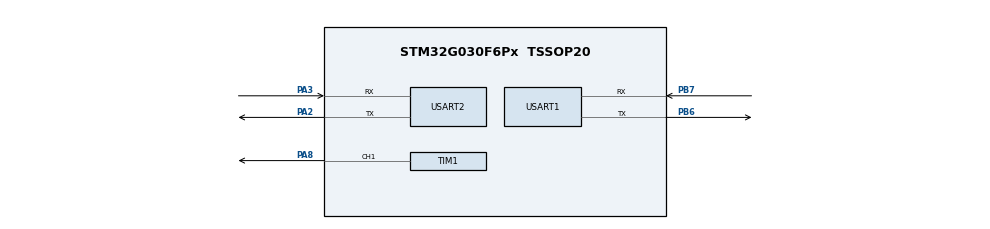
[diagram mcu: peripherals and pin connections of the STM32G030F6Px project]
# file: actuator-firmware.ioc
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Mcu.Family=STM32G0
Mcu.Name=STM32G030F6Px
Mcu.Package=TSSOP20
NVIC.TIM1_BRK_UP_TRG_COM_IRQn=true\:0\:0\:false\:false\:true\:true\:true\:true
PA14-BOOT0__PA15.StandardMode=true
PA2.Mode=Asynchronous
PA2.Signal=USART2_TX
PA3.Mode=Asynchronous
PA3.Signal=USART2_RX
PA8.Signal=S_TIM1_CH1
PB0__PB1__PB2__PA8.StandardMode=true
PB3__PB4__PB5__PB6.StandardMode=true
PB6.Mode=Asynchronous
PB6.Signal=USART1_TX
PB7.Mode=Asynchronous
PB7.Signal=USART1_RX
PB7__PB8.StandardMode=true
PC14-OSC32_IN\ (PC14)__PB9.StandardMode=true
ProjectManager.HeapSize=0x200
ProjectManager.StackSize=0x400
ProjectManager.TargetToolchain=CMake
RCC.ADCFreq_Value=64000000
RCC.AHBFreq_Value=64000000
RCC.CortexFreq_Value=64000000
RCC.EXTERNAL_CLOCK_VALUE=12288000
RCC.HCLKFreq_Value=64000000
RCC.HSE_VALUE=8000000
RCC.HSI_VALUE=16000000
RCC.LSE_VALUE=32768
RCC.SYSCLKFreq_VALUE=64000000
RCC.SYSCLKSource=RCC_SYSCLKSOURCE_PLLCLK
RCC.VCOOutputFreq_Value=128000000
SH.S_TIM1_CH1.0=TIM1_CH1,PWM Generation1 CH1
TIM1.Channel-PWM\ Generation1\ CH1=TIM_CHANNEL_1
TIM1.Period=255
TIM1.Prescaler=16
TIM1.Pulse-PWM\ Generation1\ CH1=0
USART1.VirtualMode-Asynchronous=VM_ASYNC
USART2.VirtualMode-Asynchronous=VM_ASYNC
VP_TIM1_VS_ClockSourceINT.Mode=Internal
board=custom

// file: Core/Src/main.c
/* USER CODE BEGIN Header */
/**
  ******************************************************************************
  * @file           : main.c
  * @brief          : Main program body
  ******************************************************************************
  * @attention
  *
  * Copyright (c) 2025 STMicroelectronics.
  * All rights reserved.
  *
  * This software is licensed under terms that can be found in the LICENSE file
  * in the root directory of this software component.
  * If no LICENSE file comes with this software, it is provided AS-IS.
  *
  ******************************************************************************
  */
/* USER CODE END Header */
#include "main.h"

TIM_HandleTypeDef htim1;

UART_HandleTypeDef huart1;
UART_HandleTypeDef huart2;

void SystemClock_Config(void);
static void MX_GPIO_Init(void);
static void MX_TIM1_Init(void);
static void MX_USART1_UART_Init(void);
static void MX_USART2_UART_Init(void);

/* USER CODE BEGIN 0 */
void real_main(void);

/* USER CODE END 0 */

int main(void)
{

  /* MCU Configuration--------------------------------------------------------*/

  /* Reset of all peripherals, Initializes the Flash interface and the Systick. */
  HAL_Init();

  /* Configure the system clock */
  SystemClock_Config();

  /* Initialize all configured peripherals */
  MX_GPIO_Init();
  MX_TIM1_Init();
  MX_USART1_UART_Init();
  MX_USART2_UART_Init();

  /* Infinite loop */
  while (1)
  {

    /* USER CODE BEGIN 3 */
    real_main();
  }
  /* USER CODE END 3 */
}

void SystemClock_Config(void)
{
  RCC_OscInitTypeDef RCC_OscInitStruct = {0};
  RCC_ClkInitTypeDef RCC_ClkInitStruct = {0};

  /** Configure the main internal regulator output voltage
  */
  HAL_PWREx_ControlVoltageScaling(PWR_REGULATOR_VOLTAGE_SCALE1);

  /** Initializes the RCC Oscillators according to the specified parameters
  * in the RCC_OscInitTypeDef structure.
  */
  RCC_OscInitStruct.OscillatorType = RCC_OSCILLATORTYPE_HSI;
  RCC_OscInitStruct.HSIState = RCC_HSI_ON;
  RCC_OscInitStruct.HSIDiv = RCC_HSI_DIV1;
  RCC_OscInitStruct.HSICalibrationValue = RCC_HSICALIBRATION_DEFAULT;
  RCC_OscInitStruct.PLL.PLLState = RCC_PLL_NONE;
  if (HAL_RCC_OscConfig(&RCC_OscInitStruct) != HAL_OK)
  {
    Error_Handler();
  }

  /** Initializes the CPU, AHB and APB buses clocks
  */
  RCC_ClkInitStruct.ClockType = RCC_CLOCKTYPE_HCLK|RCC_CLOCKTYPE_SYSCLK
                              |RCC_CLOCKTYPE_PCLK1;
  RCC_ClkInitStruct.SYSCLKSource = RCC_SYSCLKSOURCE_HSI;
  RCC_ClkInitStruct.AHBCLKDivider = RCC_SYSCLK_DIV1;
  RCC_ClkInitStruct.APB1CLKDivider = RCC_HCLK_DIV1;

  if (HAL_RCC_ClockConfig(&RCC_ClkInitStruct, FLASH_LATENCY_0) != HAL_OK)
  {
    Error_Handler();
  }
}

static void MX_TIM1_Init(void)
{

  TIM_ClockConfigTypeDef sClockSourceConfig = {0};
  TIM_MasterConfigTypeDef sMasterConfig = {0};
  TIM_OC_InitTypeDef sConfigOC = {0};
  TIM_BreakDeadTimeConfigTypeDef sBreakDeadTimeConfig = {0};

  htim1.Instance = TIM1;
  htim1.Init.Prescaler = 16;
  htim1.Init.CounterMode = TIM_COUNTERMODE_UP;
  htim1.Init.Period = 255;
  htim1.Init.ClockDivision = TIM_CLOCKDIVISION_DIV1;
  htim1.Init.RepetitionCounter = 0;
  htim1.Init.AutoReloadPreload = TIM_AUTORELOAD_PRELOAD_DISABLE;
  if (HAL_TIM_Base_Init(&htim1) != HAL_OK)
  {
    Error_Handler();
  }
  sClockSourceConfig.ClockSource = TIM_CLOCKSOURCE_INTERNAL;
  if (HAL_TIM_ConfigClockSource(&htim1, &sClockSourceConfig) != HAL_OK)
  {
    Error_Handler();
  }
  if (HAL_TIM_PWM_Init(&htim1) != HAL_OK)
  {
    Error_Handler();
  }
  sMasterConfig.MasterOutputTrigger = TIM_TRGO_RESET;
  sMasterConfig.MasterOutputTrigger2 = TIM_TRGO2_RESET;
  sMasterConfig.MasterSlaveMode = TIM_MASTERSLAVEMODE_DISABLE;
  if (HAL_TIMEx_MasterConfigSynchronization(&htim1, &sMasterConfig) != HAL_OK)
  {
    Error_Handler();
  }
  sConfigOC.OCMode = TIM_OCMODE_PWM1;
  sConfigOC.Pulse = 0;
  sConfigOC.OCPolarity = TIM_OCPOLARITY_HIGH;
  sConfigOC.OCNPolarity = TIM_OCNPOLARITY_HIGH;
  sConfigOC.OCFastMode = TIM_OCFAST_DISABLE;
  sConfigOC.OCIdleState = TIM_OCIDLESTATE_RESET;
  sConfigOC.OCNIdleState = TIM_OCNIDLESTATE_RESET;
  if (HAL_TIM_PWM_ConfigChannel(&htim1, &sConfigOC, TIM_CHANNEL_1) != HAL_OK)
  {
    Error_Handler();
  }
  sBreakDeadTimeConfig.OffStateRunMode = TIM_OSSR_DISABLE;
  sBreakDeadTimeConfig.OffStateIDLEMode = TIM_OSSI_DISABLE;
  sBreakDeadTimeConfig.LockLevel = TIM_LOCKLEVEL_OFF;
  sBreakDeadTimeConfig.DeadTime = 0;
  sBreakDeadTimeConfig.BreakState = TIM_BREAK_DISABLE;
  sBreakDeadTimeConfig.BreakPolarity = TIM_BREAKPOLARITY_HIGH;
  sBreakDeadTimeConfig.BreakFilter = 0;
  sBreakDeadTimeConfig.BreakAFMode = TIM_BREAK_AFMODE_INPUT;
  sBreakDeadTimeConfig.Break2State = TIM_BREAK2_DISABLE;
  sBreakDeadTimeConfig.Break2Polarity = TIM_BREAK2POLARITY_HIGH;
  sBreakDeadTimeConfig.Break2Filter = 0;
  sBreakDeadTimeConfig.Break2AFMode = TIM_BREAK_AFMODE_INPUT;
  sBreakDeadTimeConfig.AutomaticOutput = TIM_AUTOMATICOUTPUT_DISABLE;
  if (HAL_TIMEx_ConfigBreakDeadTime(&htim1, &sBreakDeadTimeConfig) != HAL_OK)
  {
    Error_Handler();
  }
  HAL_TIM_MspPostInit(&htim1);

}

static void MX_USART1_UART_Init(void)
{

  huart1.Instance = USART1;
  huart1.Init.BaudRate = 115200;
  huart1.Init.WordLength = UART_WORDLENGTH_8B;
  huart1.Init.StopBits = UART_STOPBITS_1;
  huart1.Init.Parity = UART_PARITY_NONE;
  huart1.Init.Mode = UART_MODE_TX_RX;
  huart1.Init.HwFlowCtl = UART_HWCONTROL_NONE;
  huart1.Init.OverSampling = UART_OVERSAMPLING_16;
  huart1.Init.OneBitSampling = UART_ONE_BIT_SAMPLE_DISABLE;
  huart1.Init.ClockPrescaler = UART_PRESCALER_DIV1;
  huart1.AdvancedInit.AdvFeatureInit = UART_ADVFEATURE_NO_INIT;
  if (HAL_UART_Init(&huart1) != HAL_OK)
  {
    Error_Handler();
  }
  if (HAL_UARTEx_SetTxFifoThreshold(&huart1, UART_TXFIFO_THRESHOLD_1_8) != HAL_OK)
  {
    Error_Handler();
  }
  if (HAL_UARTEx_SetRxFifoThreshold(&huart1, UART_RXFIFO_THRESHOLD_1_8) != HAL_OK)
  {
    Error_Handler();
  }
  if (HAL_UARTEx_DisableFifoMode(&huart1) != HAL_OK)
  {
    Error_Handler();
  }

}

static void MX_USART2_UART_Init(void)
{

  huart2.Instance = USART2;
  huart2.Init.BaudRate = 115200;
  huart2.Init.WordLength = UART_WORDLENGTH_8B;
  huart2.Init.StopBits = UART_STOPBITS_1;
  huart2.Init.Parity = UART_PARITY_NONE;
  huart2.Init.Mode = UART_MODE_TX_RX;
  huart2.Init.HwFlowCtl = UART_HWCONTROL_NONE;
  huart2.Init.OverSampling = UART_OVERSAMPLING_16;
  huart2.Init.OneBitSampling = UART_ONE_BIT_SAMPLE_DISABLE;
  huart2.Init.ClockPrescaler = UART_PRESCALER_DIV1;
  huart2.AdvancedInit.AdvFeatureInit = UART_ADVFEATURE_NO_INIT;
  if (HAL_UART_Init(&huart2) != HAL_OK)
  {
    Error_Handler();
  }

}

static void MX_GPIO_Init(void)
{

  /* GPIO Ports Clock Enable */
  __HAL_RCC_GPIOB_CLK_ENABLE();
  __HAL_RCC_GPIOA_CLK_ENABLE();

}

void Error_Handler(void)
{
  __disable_irq();
  while (1)
  {
  }
}
#ifdef USE_FULL_ASSERT
/**
  * @brief  Reports the name of the source file and the source line number
  *         where the assert_param error has occurred.
  * @param  file: pointer to the source file name
  * @param  line: assert_param error line source number
  * @retval None
  */
void assert_failed(uint8_t *file, uint32_t line)
{
  /* USER CODE BEGIN 6 */
  /* User can add his own implementation to report the file name and line number,
     eg: printf("Wrong parameters value: file %s on line %d\r\n", file, line) */
  /* USER CODE END 6 */
}
#endif /* USE_FULL_ASSERT */
